VERSION 5.7 ;
  NOWIREEXTENSIONATPIN ON ;
  DIVIDERCHAR "/" ;
  BUSBITCHARS "[]" ;
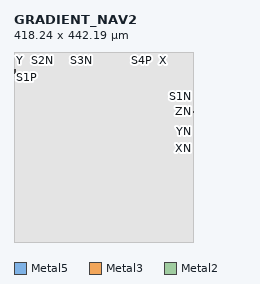
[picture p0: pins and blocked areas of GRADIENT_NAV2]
MACRO GRADIENT_NAV2
  CLASS BLOCK ;
  FOREIGN GRADIENT_NAV2 ;
  ORIGIN 0.000 0.000 ;
  SIZE 418.240 BY 442.190 ;
  PIN VDD
    DIRECTION INOUT ;
    USE POWER ;
    PORT
      LAYER Metal5 ;
        RECT 0.000 397.370 3.000 400.370 ;
    END
  END VDD
  PIN VSS
    DIRECTION INOUT ;
    USE GROUND ;
    PORT
      LAYER Metal5 ;
        RECT 0.000 391.370 3.000 394.370 ;
    END
  END VSS
  PIN XP
    DIRECTION OUTPUT ;
    USE SIGNAL ;
    PORT
      LAYER Metal3 ;
        RECT 417.720 211.820 418.240 212.100 ;
    END
  END XP
  PIN X
    DIRECTION OUTPUT ;
    USE SIGNAL ;
    PORT
      LAYER Metal2 ;
        RECT 347.900 441.670 348.180 442.190 ;
    END
  END X
  PIN XN
    DIRECTION OUTPUT ;
    USE SIGNAL ;
    PORT
      LAYER Metal3 ;
        RECT 417.720 216.860 418.240 217.140 ;
    END
  END XN
  PIN YP
    DIRECTION OUTPUT ;
    USE SIGNAL ;
    PORT
      LAYER Metal3 ;
        RECT 417.720 252.140 418.240 252.420 ;
    END
  END YP
  PIN Y
    DIRECTION OUTPUT ;
    USE SIGNAL ;
    PORT
      LAYER Metal3 ;
        RECT 0.000 408.380 0.520 408.660 ;
    END
  END Y
  PIN YN
    DIRECTION OUTPUT ;
    USE SIGNAL ;
    PORT
      LAYER Metal3 ;
        RECT 417.720 257.180 418.240 257.460 ;
    END
  END YN
  PIN ZP
    DIRECTION OUTPUT ;
    USE SIGNAL ;
    PORT
      LAYER Metal3 ;
        RECT 417.720 297.500 418.240 297.780 ;
    END
  END ZP
  PIN Z
    DIRECTION OUTPUT ;
    USE SIGNAL ;
    PORT
      LAYER Metal2 ;
        RECT 60.620 441.670 60.900 442.190 ;
    END
  END Z
  PIN ZN
    DIRECTION OUTPUT ;
    USE SIGNAL ;
    PORT
      LAYER Metal3 ;
        RECT 417.720 302.540 418.240 302.820 ;
    END
  END ZN
  PIN S2P
    DIRECTION INPUT ;
    USE SIGNAL ;
    PORT
      LAYER Metal2 ;
        RECT 111.020 441.670 111.300 442.190 ;
    END
  END S2P
  PIN S2N
    DIRECTION INPUT ;
    USE SIGNAL ;
    PORT
      LAYER Metal2 ;
        RECT 65.660 441.670 65.940 442.190 ;
    END
  END S2N
  PIN S4P
    DIRECTION INPUT ;
    USE SIGNAL ;
    PORT
      LAYER Metal2 ;
        RECT 297.500 441.670 297.780 442.190 ;
    END
  END S4P
  PIN S4N
    DIRECTION INPUT ;
    USE SIGNAL ;
    PORT
      LAYER Metal2 ;
        RECT 252.140 441.670 252.420 442.190 ;
    END
  END S4N
  PIN S3P
    DIRECTION INPUT ;
    USE SIGNAL ;
    PORT
      LAYER Metal2 ;
        RECT 201.740 441.670 202.020 442.190 ;
    END
  END S3P
  PIN S3N
    DIRECTION INPUT ;
    USE SIGNAL ;
    PORT
      LAYER Metal2 ;
        RECT 156.380 441.670 156.660 442.190 ;
    END
  END S3N
  PIN S1P
    DIRECTION INPUT ;
    USE SIGNAL ;
    PORT
      LAYER Metal3 ;
        RECT 0.000 383.180 0.520 383.460 ;
    END
  END S1P
  PIN S1N
    DIRECTION INPUT ;
    USE SIGNAL ;
    PORT
      LAYER Metal3 ;
        RECT 417.720 337.820 418.240 338.100 ;
    END
  END S1N
  OBS
      LAYER Metal1 ;
        RECT 0.000 0.000 418.240 442.190 ;
      LAYER Metal2 ;
        RECT 0.000 0.000 418.240 442.190 ;
      LAYER Metal3 ;
        RECT 0.000 0.000 418.240 442.190 ;
      LAYER Metal4 ;
        RECT 0.000 0.000 418.240 442.190 ;
      LAYER Metal5 ;
        RECT 0.000 0.000 418.240 442.190 ;
  END
END GRADIENT_NAV2
